VERSION 5.7 ;
BUSBITCHARS "[]" ;
DIVIDERCHAR "/" ;
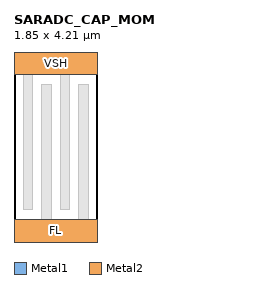
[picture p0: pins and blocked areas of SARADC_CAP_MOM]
MACRO SARADC_CAP_MOM
  CLASS BLOCK ;
  FOREIGN SARADC_CAP_MOM ;
  ORIGIN 0.000 0.000 ;
  SIZE 1.850 BY 4.210 ;
  SYMMETRY X Y ;
  PIN VSH
    DIRECTION INOUT ;
    USE SIGNAL ;
    PORT
      LAYER Metal1 ;
        RECT 0.000 3.710 1.850 4.210 ;
      LAYER Metal2 ;
        RECT 0.000 3.710 1.850 4.210 ;
    END
  END VSH
  PIN FL
    DIRECTION INOUT ;
    USE SIGNAL ;
    PORT
      LAYER Metal1 ;
        RECT 0.000 0.000 1.850 0.500 ;
      LAYER Metal2 ;
        RECT 0.000 0.000 1.850 0.500 ;
    END
  END FL
  OBS
      LAYER Metal1 ;
        RECT 0.210 0.710 0.410 3.710 ;
      LAYER Metal2 ;
        RECT 0.210 0.710 0.410 3.710 ;
      LAYER Metal1 ;
        RECT 0.620 0.500 0.820 3.500 ;
      LAYER Metal2 ;
        RECT 0.620 0.500 0.820 3.500 ;
      LAYER Metal1 ;
        RECT 1.030 0.710 1.230 3.710 ;
      LAYER Metal2 ;
        RECT 1.030 0.710 1.230 3.710 ;
      LAYER Metal1 ;
        RECT 1.440 0.500 1.640 3.500 ;
      LAYER Metal2 ;
        RECT 1.440 0.500 1.640 3.500 ;
  END
END SARADC_CAP_MOM
END LIBRARY
